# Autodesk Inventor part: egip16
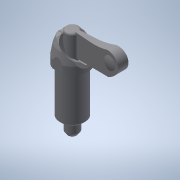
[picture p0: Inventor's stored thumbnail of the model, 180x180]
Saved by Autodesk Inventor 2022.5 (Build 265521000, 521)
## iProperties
Created: 2016-12
Part Number: egip16
Material: 一般
Document SubType Name: Modeling
Designer: imaocorp
Density: 1 g/cm^3
Appearance: 既定
Author: imaocorp
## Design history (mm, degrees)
node "egip16.x_t1"
node "HI_NT PMT.200-8-M16x1.5-A-1"
node "Base1"
